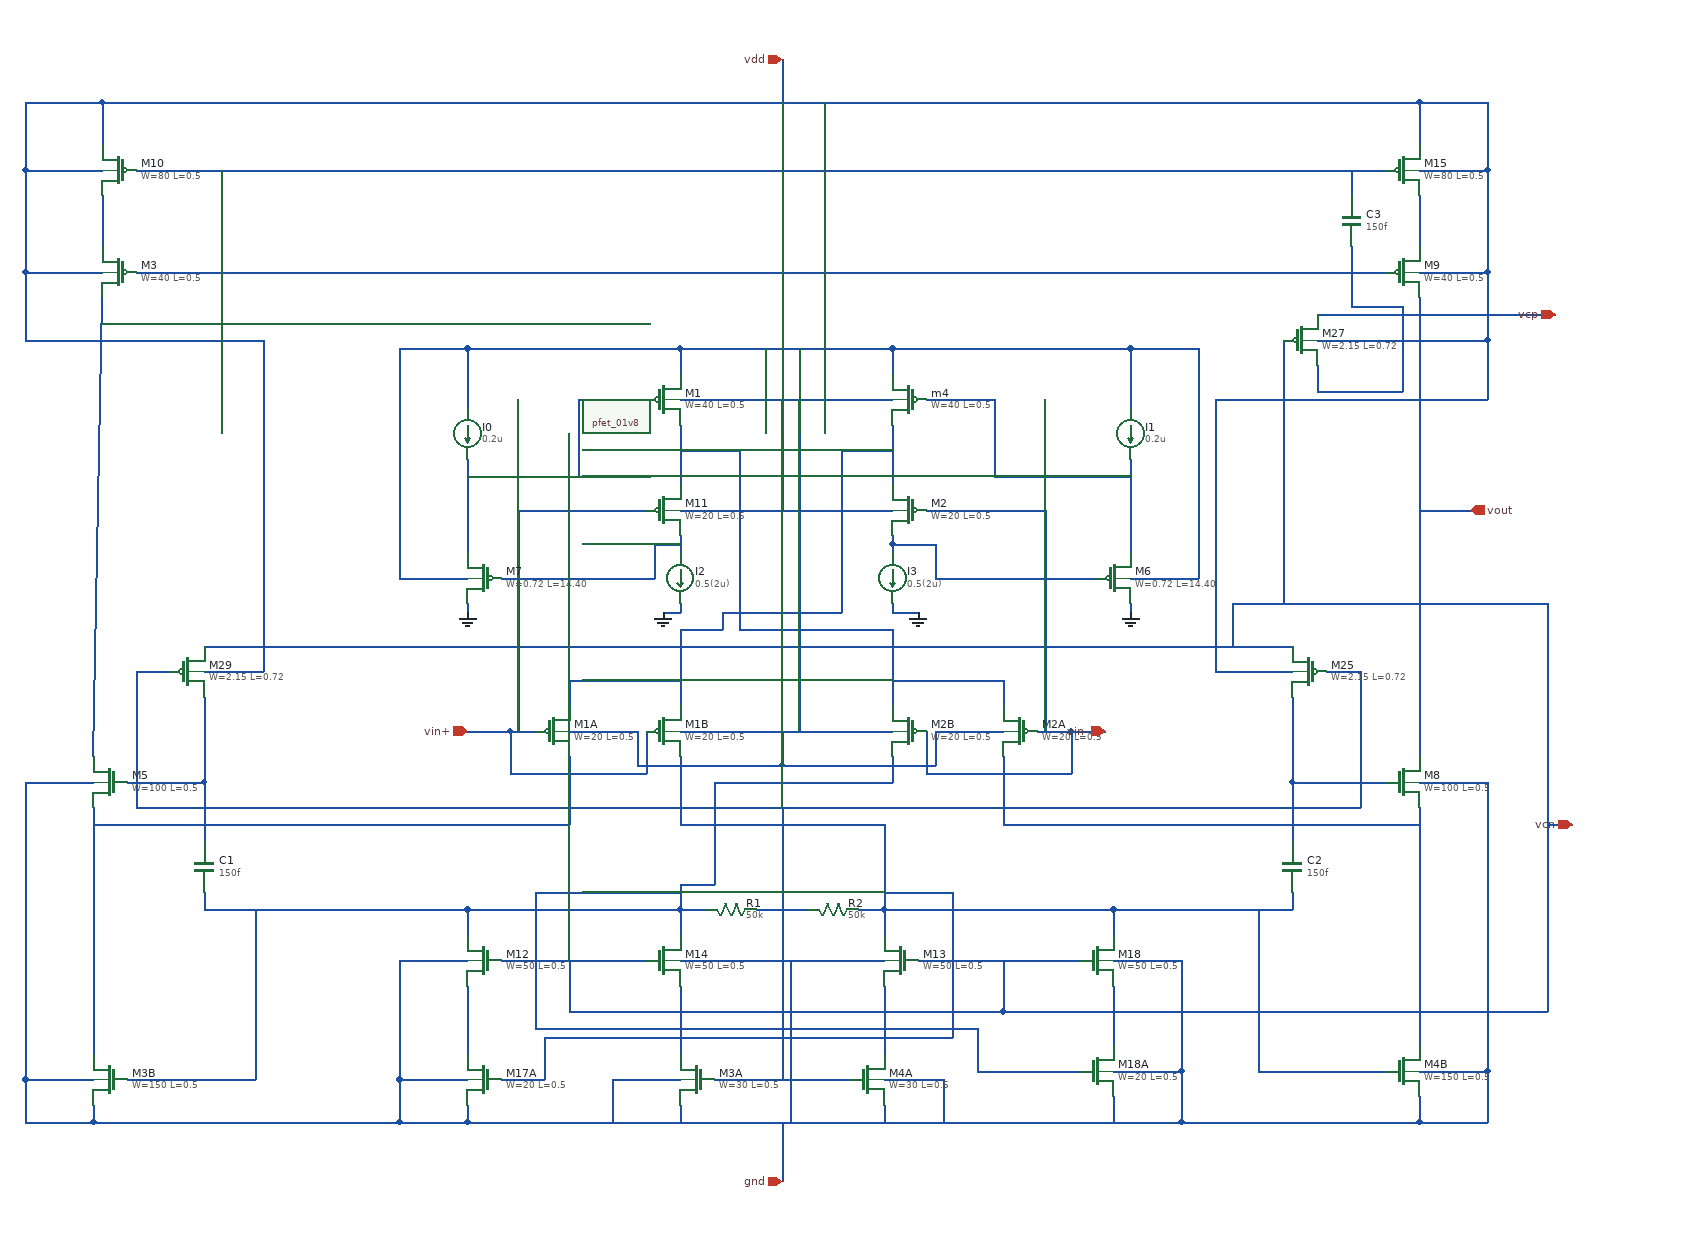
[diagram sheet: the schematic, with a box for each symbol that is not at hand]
v {xschem version=3.4.8RC file_version=1.3}
G {}
K {}
V {}
S {.include /home/aryan_r_gowda/VLSI/pdk/volare/sky130/versions/0fe599b2afb6708d281543108caf8310912f54af/sky130A/libs.tech/ngspice/sky130.lib.spice
.lib /home/aryan_r_gowda/VLSI/pdk/volare/sky130/versions/0fe599b2afb6708d281543108caf8310912f54af/sky130A/libs.tech/ngspice/sky130.lib.spice tt}
F {}
E {}
N -120 -270 -120 -240 {lab=vdd}
N -120 -270 130 -270 {lab=vdd}
N 130 -270 130 -240 {lab=vdd}
N 130 -180 130 -110 {lab=#net1}
N 260 120 260 150 {lab=#net2}
N 130 120 260 120 {lab=#net2}
N -250 120 -250 150 {lab=#net1}
N -250 120 -120 120 {lab=#net1}
N 130 100 130 150 {lab=#net2}
N -120 -150 -80 -150 {lab=#net2}
N -120 100 -120 150 {lab=#net1}
N 90 -150 130 -150 {lab=#net1}
N -370 -270 -370 -200 {lab=vdd}
N -370 -270 -120 -270 {lab=vdd}
N 410 -270 410 -200 {lab=vdd}
N 130 -270 330 -270 {lab=vdd}
N -370 -140 -370 -30 {lab=#net3}
N 410 -140 410 -30 {lab=#net4}
N 130 -50 130 -40 {lab=#net5}
N -160 180 -160 230 {lab=vin+}
N -320 230 -160 230 {lab=vin+}
N -320 180 -320 230 {lab=vin+}
N -320 180 -290 180 {lab=vin+}
N -370 180 -320 180 {lab=vin+}
N -120 60 -120 100 {lab=#net1}
N 130 60 130 100 {lab=#net2}
N 170 180 170 230 {lab=vin-}
N 170 230 340 230 {lab=vin-}
N 340 180 340 230 {lab=vin-}
N 300 180 340 180 {lab=vin-}
N 340 180 380 180 {lab=vin-}
N 330 -270 410 -270 {lab=vdd}
N 170 -80 310 -80 {lab=vin-}
N 310 -80 310 180 {lab=vin-}
N 170 -210 250 -210 {lab=#net4}
N 320 -120 410 -120 {lab=#net4}
N -240 -210 -160 -210 {lab=#net3}
N -370 -120 -310 -120 {lab=#net3}
N -370 30 -370 40 {lab=0}
N -120 30 -120 40 {lab=0}
N -140 40 -120 40 {lab=0}
N 410 30 410 40 {lab=0}
N -120 -210 130 -210 {lab=vdd}
N -120 180 130 180 {lab=vdd}
N -120 -180 -120 -110 {lab=#net2}
N -310 -80 -160 -80 {lab=vin+}
N -310 -80 -310 -60 {lab=vin+}
N -310 -60 -310 180 {lab=vin+}
N -120 -80 130 -80 {lab=vdd}
N -450 -0 -370 -0 {lab=vdd}
N -450 -270 -370 -270 {lab=vdd}
N 410 -0 490 -0 {lab=vdd}
N 490 -270 490 -0 {lab=vdd}
N 410 -270 490 -270 {lab=vdd}
N -250 180 -180 180 {lab=vdd}
N -180 180 -170 180 {lab=vdd}
N -170 180 -170 220 {lab=vdd}
N -170 220 -0 220 {lab=vdd}
N -0 180 -0 220 {lab=vdd}
N 180 180 260 180 {lab=vdd}
N 180 180 180 220 {lab=vdd}
N 0 220 180 220 {lab=vdd}
N -20 -270 -20 -210 {lab=vdd}
N -0 -270 0 -80 {lab=vdd}
N 20 -270 20 180 {lab=vdd}
N -120 480 -120 560 {lab=#net6}
N 120 480 120 550 {lab=#net7}
N 390 480 390 550 {lab=#net8}
N 160 450 350 450 {lab=vcn}
N -330 450 -160 450 {lab=vcn}
N -370 620 -370 640 {lab=gnd}
N -360 640 400 640 {lab=gnd}
N 390 610 390 640 {lab=gnd}
N -120 620 -120 640 {lab=gnd}
N -80 590 80 590 {lab=#net9}
N 120 550 120 560 {lab=#net7}
N 120 620 120 640 {lab=gnd}
N -250 450 -250 510 {lab=vcn}
N -120 390 -120 420 {lab=#net10}
N -120 390 -90 390 {lab=#net10}
N -30 390 30 390 {lab=#net9}
N 90 390 120 390 {lab=#net11}
N 120 390 120 420 {lab=#net11}
N -0 390 -0 590 {lab=#net9}
N -450 450 -370 450 {lab=gnd}
N -450 450 -450 590 {lab=gnd}
N -450 590 -370 590 {lab=gnd}
N -450 590 -450 640 {lab=gnd}
N -450 640 -370 640 {lab=gnd}
N -120 450 120 450 {lab=gnd}
N 10 450 120 450 {lab=gnd}
N 10 450 10 640 {lab=gnd}
N -200 590 -120 590 {lab=gnd}
N -200 590 -200 640 {lab=gnd}
N 120 590 190 590 {lab=gnd}
N 190 590 190 640 {lab=gnd}
N 390 450 470 450 {lab=gnd}
N 470 450 470 580 {lab=gnd}
N 390 580 470 580 {lab=gnd}
N 470 580 470 640 {lab=gnd}
N 390 640 470 640 {lab=gnd}
N -120 210 -120 240 {lab=#net11}
N 130 210 130 240 {lab=#net10}
N -120 360 -120 390 {lab=#net10}
N -370 390 -370 420 {lab=#net10}
N -370 390 -120 390 {lab=#net10}
N 390 390 390 420 {lab=#net11}
N 120 390 390 390 {lab=#net11}
N -810 620 -810 640 {lab=gnd}
N -810 640 -450 640 {lab=gnd}
N 750 360 750 550 {lab=#net12}
N 750 610 750 640 {lab=gnd}
N 470 640 750 640 {lab=gnd}
N -680 390 -370 390 {lab=#net10}
N 390 390 600 390 {lab=#net11}
N -770 590 -740 590 {lab=#net10}
N -250 210 -250 290 {lab=#net13}
N -810 290 -250 290 {lab=#net13}
N 750 270 750 360 {lab=#net12}
N 260 210 260 290 {lab=#net12}
N 260 290 750 290 {lab=#net12}
N 600 370 600 390 {lab=#net11}
N -680 370 -680 390 {lab=#net10}
N 680 580 710 580 {lab=#net11}
N 600 240 600 310 {lab=#net14}
N 600 240 710 240 {lab=#net14}
N -680 240 -680 310 {lab=#net15}
N -770 240 -680 240 {lab=#net15}
N -890 240 -810 240 {lab=gnd}
N -890 240 -890 590 {lab=gnd}
N -890 590 -810 590 {lab=gnd}
N 750 580 830 580 {lab=gnd}
N 830 240 830 580 {lab=gnd}
N 750 240 830 240 {lab=gnd}
N -890 590 -890 640 {lab=gnd}
N -890 640 -810 640 {lab=gnd}
N 750 640 830 640 {lab=gnd}
N 830 580 830 640 {lab=gnd}
N 750 -330 750 210 {lab=vout}
N 750 -450 750 -390 {lab=#net16}
N -760 -360 710 -360 {lab=#net17}
N -760 -480 710 -480 {lab=#net18}
N -810 210 -800 -330 {lab=#net19}
N -800 -450 -800 -390 {lab=#net20}
N -800 -560 -800 -510 {lab=vdd}
N -800 -560 750 -560 {lab=vdd}
N 750 -560 750 -510 {lab=vdd}
N -660 -480 -660 -300 {lab=#net18}
N -800 -300 -660 -300 {lab=#net18}
N 600 140 600 240 {lab=#net14}
N 630 -250 630 -220 {lab=#net17}
N 630 -220 730 -220 {lab=#net17}
N 730 -300 730 -220 {lab=#net17}
N 730 -320 730 -300 {lab=#net17}
N 670 -320 730 -320 {lab=#net17}
N 670 -360 670 -320 {lab=#net17}
N 670 -390 670 -360 {lab=#net17}
N 670 -480 670 -450 {lab=#net18}
N -120 -50 -120 -30 {lab=#net21}
N -330 -0 -150 0 {lab=#net21}
N -150 -40 -150 0 {lab=#net21}
N -150 -40 -120 -40 {lab=#net21}
N 180 -0 370 -0 {lab=#net5}
N 180 -40 180 -0 {lab=#net5}
N 130 -40 130 -30 {lab=#net5}
N 130 -40 180 -40 {lab=#net5}
N 130 30 130 40 {lab=0}
N 130 40 160 40 {lab=0}
N -680 160 -680 240 {lab=#net15}
N 750 -480 830 -480 {lab=vdd}
N 830 -480 830 -360 {lab=vdd}
N 750 -360 830 -360 {lab=vdd}
N 630 -280 830 -280 {lab=vdd}
N 830 -360 830 -280 {lab=vdd}
N -890 -360 -800 -360 {lab=vdd}
N -890 -480 -890 -360 {lab=vdd}
N -890 -480 -800 -480 {lab=vdd}
N -890 -560 -890 -480 {lab=vdd}
N -890 -560 -800 -560 {lab=vdd}
N 830 -560 830 -480 {lab=vdd}
N 750 -560 830 -560 {lab=vdd}
N 510 110 600 110 {lab=vdd}
N 510 -210 510 110 {lab=vdd}
N 510 -210 830 -210 {lab=vdd}
N 830 -280 830 -210 {lab=vdd}
N -890 -280 -610 -280 {lab=vdd}
N -890 -360 -890 -280 {lab=vdd}
N -0 -610 0 -560 {lab=vdd}
N 0 640 0 710 {lab=gnd}
N -250 510 260 510 {lab=vcn}
N 260 450 260 510 {lab=vcn}
N 260 510 900 510 {lab=vcn}
N -680 140 -680 160 {lab=#net15}
N -680 80 600 80 {lab=vcn}
N -680 110 -610 110 {lab=vdd}
N -610 -280 -610 110 {lab=vdd}
N 530 30 530 80 {lab=vcn}
N 530 30 900 30 {lab=vcn}
N 900 30 900 510 {lab=vcn}
N 900 290 930 290 {lab=vcn}
N 590 -280 590 30 {lab=vcn}
N 630 -310 910 -310 {lab=vcp}
N 750 -80 810 -80 {lab=vout}
N -330 590 -280 590 {lab=#net11}
N -280 540 -280 590 {lab=#net11}
N -280 540 200 540 {lab=#net11}
N 200 370 200 540 {lab=#net11}
N 230 580 350 580 {lab=#net10}
N 230 530 230 580 {lab=#net10}
N -290 530 230 530 {lab=#net10}
N -290 370 -290 530 {lab=#net10}
N -760 110 -720 110 {lab=#net9}
N 640 110 670 110 {lab=#net9}
N 50 -560 50 -270 {lab=vdd}
N -370 480 -370 560 {lab=#net22}
N -450 -10 -450 -0 {lab=vdd}
N -450 -270 -450 -10 {lab=vdd}
N -370 640 -360 640 {lab=gnd}
N -810 270 -810 560 {lab=#net13}
N -760 110 -760 140 {lab=#net9}
N -760 140 -760 210 {lab=#net9}
N -760 210 -760 270 {lab=#net9}
N -760 270 680 270 {lab=#net9}
N 680 110 680 270 {lab=#net9}
N 670 110 680 110 {lab=#net9}
N -0 270 0 390 {lab=#net9}
N -290 370 -120 370 {lab=#net10}
N 120 370 200 370 {lab=#net11}
N -740 590 -620 590 {lab=#net10}
N -620 390 -620 590 {lab=#net10}
N 560 580 680 580 {lab=#net11}
N 560 390 560 580 {lab=#net11}
N -120 240 -120 290 {lab=#net11}
N -120 290 120 290 {lab=#net11}
N 120 290 120 390 {lab=#net11}
N -80 240 130 240 {lab=#net10}
N -80 240 -80 360 {lab=#net10}
N -120 360 -80 360 {lab=#net10}
N -80 -150 -50 -150 {lab=#net2}
N -50 -150 -50 60 {lab=#net2}
N -50 60 130 60 {lab=#net2}
N -120 60 -70 60 {lab=#net1}
N -70 40 -70 60 {lab=#net1}
N -70 40 70 40 {lab=#net1}
N 70 -150 70 40 {lab=#net1}
N 70 -150 90 -150 {lab=#net1}
N -310 -120 -240 -120 {lab=#net3}
N -240 -210 -240 -120 {lab=#net3}
N 250 -120 320 -120 {lab=#net4}
N 250 -210 250 -120 {lab=#net4}
C {sky130_fd_pr/doc/pfet_01v8.svg} -120 -180 0 0 {}
C {sky130_fd_pr/pfet_01v8.sym} -140 -210 0 0 {name=M1
W=40
L=0.5
nf=1
mult=1
ad="'int((nf+1)/2) * W/nf * 0.29'" 
pd="'2*int((nf+1)/2) * (W/nf + 0.29)'"
as="'int((nf+2)/2) * W/nf * 0.29'" 
ps="'2*int((nf+2)/2) * (W/nf + 0.29)'"
nrd="'0.29 / W'" nrs="'0.29 / W'"
sa=0 sb=0 sd=0
model=pfet_01v8
spiceprefix=X
}
C {sky130_fd_pr/pfet_01v8.sym} -140 180 0 0 {name=M1B
W=20
L=0.5
nf=1
mult=1
ad="'int((nf+1)/2) * W/nf * 0.29'" 
pd="'2*int((nf+1)/2) * (W/nf + 0.29)'"
as="'int((nf+2)/2) * W/nf * 0.29'" 
ps="'2*int((nf+2)/2) * (W/nf + 0.29)'"
nrd="'0.29 / W'" nrs="'0.29 / W'"
sa=0 sb=0 sd=0
model=pfet_01v8
spiceprefix=X
}
C {sky130_fd_pr/pfet_01v8.sym} 150 -80 0 1 {name=M2

W=20
L=0.5
nf=1
mult=1
ad="'int((nf+1)/2) * W/nf * 0.29'" 
pd="'2*int((nf+1)/2) * (W/nf + 0.29)'"
as="'int((nf+2)/2) * W/nf * 0.29'" 
ps="'2*int((nf+2)/2) * (W/nf + 0.29)'"
nrd="'0.29 / W'" nrs="'0.29 / W'"
sa=0 sb=0 sd=0
model=pfet_01v8
spiceprefix=X
}
C {sky130_fd_pr/pfet_01v8.sym} 150 180 0 1 {name=M2B
W=20
L=0.5
nf=1
mult=1
ad="'int((nf+1)/2) * W/nf * 0.29'" 
pd="'2*int((nf+1)/2) * (W/nf + 0.29)'"
as="'int((nf+2)/2) * W/nf * 0.29'" 
ps="'2*int((nf+2)/2) * (W/nf + 0.29)'"
nrd="'0.29 / W'" nrs="'0.29 / W'"
sa=0 sb=0 sd=0
model=pfet_01v8
spiceprefix=X
}
C {sky130_fd_pr/pfet_01v8.sym} 390 0 0 0 {name=M6
W=0.72
L=14.40
nf=1
mult=1
ad="'int((nf+1)/2) * W/nf * 0.29'" 
pd="'2*int((nf+1)/2) * (W/nf + 0.29)'"
as="'int((nf+2)/2) * W/nf * 0.29'" 
ps="'2*int((nf+2)/2) * (W/nf + 0.29)'"
nrd="'0.29 / W'" nrs="'0.29 / W'"
sa=0 sb=0 sd=0
model=pfet_01v8
spiceprefix=X
}
C {sky130_fd_pr/pfet_01v8.sym} -350 0 0 1 {name=M7
W=0.72
L=14.40
nf=1
mult=1
ad="'int((nf+1)/2) * W/nf * 0.29'" 
pd="'2*int((nf+1)/2) * (W/nf + 0.29)'"
as="'int((nf+2)/2) * W/nf * 0.29'" 
ps="'2*int((nf+2)/2) * (W/nf + 0.29)'"
nrd="'0.29 / W'" nrs="'0.29 / W'"
sa=0 sb=0 sd=0
model=pfet_01v8
spiceprefix=X
}
C {sky130_fd_pr/pfet_01v8.sym} 150 -210 0 1 {name=m4
W=40
L=0.5
nf=1
mult=1
ad="'int((nf+1)/2) * W/nf * 0.29'" 
pd="'2*int((nf+1)/2) * (W/nf + 0.29)'"
as="'int((nf+2)/2) * W/nf * 0.29'" 
ps="'2*int((nf+2)/2) * (W/nf + 0.29)'"
nrd="'0.29 / W'" nrs="'0.29 / W'"
sa=0 sb=0 sd=0
model=pfet_01v8
spiceprefix=X
}
C {sky130_fd_pr/pfet_01v8.sym} -270 180 0 0 {name=M1A
W=20
L=0.5
nf=1
mult=1
ad="'int((nf+1)/2) * W/nf * 0.29'" 
pd="'2*int((nf+1)/2) * (W/nf + 0.29)'"
as="'int((nf+2)/2) * W/nf * 0.29'" 
ps="'2*int((nf+2)/2) * (W/nf + 0.29)'"
nrd="'0.29 / W'" nrs="'0.29 / W'"
sa=0 sb=0 sd=0
model=pfet_01v8
spiceprefix=X
}
C {sky130_fd_pr/pfet_01v8.sym} 280 180 0 1 {name=M2A
W=20
L=0.5
nf=1
mult=1
ad="'int((nf+1)/2) * W/nf * 0.29'" 
pd="'2*int((nf+1)/2) * (W/nf + 0.29)'"
as="'int((nf+2)/2) * W/nf * 0.29'" 
ps="'2*int((nf+2)/2) * (W/nf + 0.29)'"
nrd="'0.29 / W'" nrs="'0.29 / W'"
sa=0 sb=0 sd=0
model=pfet_01v8
spiceprefix=X
}
C {isource.sym} -370 -170 0 0 {name=I0 value=0.2u}
C {isource.sym} 410 -170 0 0 {name=I1 value=0.2u}
C {isource.sym} -120 0 0 0 {name=I2 value=0.5(2u)}
C {isource.sym} 130 0 0 0 {name=I3 value=0.5(2u)}
C {gnd.sym} -370 40 0 0 {name=l1 lab=0}
C {gnd.sym} -140 40 0 0 {name=l2 lab=0}
C {gnd.sym} 410 40 0 0 {name=l4 lab=0}
C {sky130_fd_pr/nfet_01v8.sym} -350 590 0 1 {name=M17A
W=20
L=0.5
nf=1 
mult=1
ad="'int((nf+1)/2) * W/nf * 0.29'" 
pd="'2*int((nf+1)/2) * (W/nf + 0.29)'"
as="'int((nf+2)/2) * W/nf * 0.29'" 
ps="'2*int((nf+2)/2) * (W/nf + 0.29)'"
nrd="'0.29 / W'" nrs="'0.29 / W'"
sa=0 sb=0 sd=0
model=nfet_01v8
spiceprefix=X
}
C {sky130_fd_pr/nfet_01v8.sym} -350 450 0 1 {name=M12
W=50
L=0.5
nf=1 
mult=1
ad="'int((nf+1)/2) * W/nf * 0.29'" 
pd="'2*int((nf+1)/2) * (W/nf + 0.29)'"
as="'int((nf+2)/2) * W/nf * 0.29'" 
ps="'2*int((nf+2)/2) * (W/nf + 0.29)'"
nrd="'0.29 / W'" nrs="'0.29 / W'"
sa=0 sb=0 sd=0
model=nfet_01v8
spiceprefix=X
}
C {sky130_fd_pr/nfet_01v8.sym} 140 450 0 1 {name=M13
W=50
L=0.5
nf=1 
mult=1
ad="'int((nf+1)/2) * W/nf * 0.29'" 
pd="'2*int((nf+1)/2) * (W/nf + 0.29)'"
as="'int((nf+2)/2) * W/nf * 0.29'" 
ps="'2*int((nf+2)/2) * (W/nf + 0.29)'"
nrd="'0.29 / W'" nrs="'0.29 / W'"
sa=0 sb=0 sd=0
model=nfet_01v8
spiceprefix=X
}
C {sky130_fd_pr/nfet_01v8.sym} -140 450 0 0 {name=M14
W=50
L=0.5
nf=1 
mult=1
ad="'int((nf+1)/2) * W/nf * 0.29'" 
pd="'2*int((nf+1)/2) * (W/nf + 0.29)'"
as="'int((nf+2)/2) * W/nf * 0.29'" 
ps="'2*int((nf+2)/2) * (W/nf + 0.29)'"
nrd="'0.29 / W'" nrs="'0.29 / W'"
sa=0 sb=0 sd=0
model=nfet_01v8
spiceprefix=X
}
C {sky130_fd_pr/nfet_01v8.sym} 100 590 0 0 {name=M4A
W=30
L=0.5
nf=1 
mult=1
ad="'int((nf+1)/2) * W/nf * 0.29'" 
pd="'2*int((nf+1)/2) * (W/nf + 0.29)'"
as="'int((nf+2)/2) * W/nf * 0.29'" 
ps="'2*int((nf+2)/2) * (W/nf + 0.29)'"
nrd="'0.29 / W'" nrs="'0.29 / W'"
sa=0 sb=0 sd=0
model=nfet_01v8
spiceprefix=X
}
C {sky130_fd_pr/nfet_01v8.sym} -100 590 0 1 {name=M3A
W=30
L=0.5
nf=1 
mult=1
ad="'int((nf+1)/2) * W/nf * 0.29'" 
pd="'2*int((nf+1)/2) * (W/nf + 0.29)'"
as="'int((nf+2)/2) * W/nf * 0.29'" 
ps="'2*int((nf+2)/2) * (W/nf + 0.29)'"
nrd="'0.29 / W'" nrs="'0.29 / W'"
sa=0 sb=0 sd=0
model=nfet_01v8
spiceprefix=X
}
C {sky130_fd_pr/nfet_01v8.sym} 370 580 0 0 {name=M18A
W=20
L=0.5
nf=1 
mult=1
ad="'int((nf+1)/2) * W/nf * 0.29'" 
pd="'2*int((nf+1)/2) * (W/nf + 0.29)'"
as="'int((nf+2)/2) * W/nf * 0.29'" 
ps="'2*int((nf+2)/2) * (W/nf + 0.29)'"
nrd="'0.29 / W'" nrs="'0.29 / W'"
sa=0 sb=0 sd=0
model=nfet_01v8
spiceprefix=X
}
C {sky130_fd_pr/nfet_01v8.sym} 370 450 0 0 {name=M18
W=50
L=0.5
nf=1 
mult=1
ad="'int((nf+1)/2) * W/nf * 0.29'" 
pd="'2*int((nf+1)/2) * (W/nf + 0.29)'"
as="'int((nf+2)/2) * W/nf * 0.29'" 
ps="'2*int((nf+2)/2) * (W/nf + 0.29)'"
nrd="'0.29 / W'" nrs="'0.29 / W'"
sa=0 sb=0 sd=0
model=nfet_01v8
spiceprefix=X
}
C {res.sym} -60 390 1 0 {name=R1
value=50k
footprint=1206
device=resistor
m=1}
C {res.sym} 60 390 1 0 {name=R2
value=50k
footprint=1206
device=resistor
m=1}
C {sky130_fd_pr/nfet_01v8.sym} 730 240 0 0 {name=M8
W=100
L=0.5
nf=1 
mult=1
ad="'int((nf+1)/2) * W/nf * 0.29'" 
pd="'2*int((nf+1)/2) * (W/nf + 0.29)'"
as="'int((nf+2)/2) * W/nf * 0.29'" 
ps="'2*int((nf+2)/2) * (W/nf + 0.29)'"
nrd="'0.29 / W'" nrs="'0.29 / W'"
sa=0 sb=0 sd=0
model=nfet_01v8
spiceprefix=X
}
C {sky130_fd_pr/nfet_01v8.sym} 730 580 0 0 {name=M4B
W=150
L=0.5
nf=1 
mult=1
ad="'int((nf+1)/2) * W/nf * 0.29'" 
pd="'2*int((nf+1)/2) * (W/nf + 0.29)'"
as="'int((nf+2)/2) * W/nf * 0.29'" 
ps="'2*int((nf+2)/2) * (W/nf + 0.29)'"
nrd="'0.29 / W'" nrs="'0.29 / W'"
sa=0 sb=0 sd=0
model=nfet_01v8
spiceprefix=X
}
C {sky130_fd_pr/nfet_01v8.sym} -790 240 0 1 {name=M5
W=100
L=0.5
nf=1 
mult=1
ad="'int((nf+1)/2) * W/nf * 0.29'" 
pd="'2*int((nf+1)/2) * (W/nf + 0.29)'"
as="'int((nf+2)/2) * W/nf * 0.29'" 
ps="'2*int((nf+2)/2) * (W/nf + 0.29)'"
nrd="'0.29 / W'" nrs="'0.29 / W'"
sa=0 sb=0 sd=0
model=nfet_01v8
spiceprefix=X
}
C {sky130_fd_pr/nfet_01v8.sym} -790 590 0 1 {name=M3B
W=150
L=0.5
nf=1 
mult=1
ad="'int((nf+1)/2) * W/nf * 0.29'" 
pd="'2*int((nf+1)/2) * (W/nf + 0.29)'"
as="'int((nf+2)/2) * W/nf * 0.29'" 
ps="'2*int((nf+2)/2) * (W/nf + 0.29)'"
nrd="'0.29 / W'" nrs="'0.29 / W'"
sa=0 sb=0 sd=0
model=nfet_01v8
spiceprefix=X
}
C {capa.sym} -680 340 0 0 {name=C1
m=1
value=150f
footprint=1206
device="ceramic capacitor"}
C {capa.sym} 600 340 0 0 {name=C2
m=1
value=150f
footprint=1206
device="ceramic capacitor"}
C {sky130_fd_pr/pfet_01v8.sym} -780 -480 0 1 {name=M10
W=80
L=0.5
nf=1
mult=1
ad="'int((nf+1)/2) * W/nf * 0.29'" 
pd="'2*int((nf+1)/2) * (W/nf + 0.29)'"
as="'int((nf+2)/2) * W/nf * 0.29'" 
ps="'2*int((nf+2)/2) * (W/nf + 0.29)'"
nrd="'0.29 / W'" nrs="'0.29 / W'"
sa=0 sb=0 sd=0
model=pfet_01v8
spiceprefix=X
}
C {sky130_fd_pr/pfet_01v8.sym} -780 -360 0 1 {name=M3
W=40
L=0.5
nf=1
mult=1
ad="'int((nf+1)/2) * W/nf * 0.29'" 
pd="'2*int((nf+1)/2) * (W/nf + 0.29)'"
as="'int((nf+2)/2) * W/nf * 0.29'" 
ps="'2*int((nf+2)/2) * (W/nf + 0.29)'"
nrd="'0.29 / W'" nrs="'0.29 / W'"
sa=0 sb=0 sd=0
model=pfet_01v8
spiceprefix=X
}
C {sky130_fd_pr/pfet_01v8.sym} 620 110 0 1 {name=M25
W=2.15
L=0.72
nf=1
mult=1
ad="'int((nf+1)/2) * W/nf * 0.29'" 
pd="'2*int((nf+1)/2) * (W/nf + 0.29)'"
as="'int((nf+2)/2) * W/nf * 0.29'" 
ps="'2*int((nf+2)/2) * (W/nf + 0.29)'"
nrd="'0.29 / W'" nrs="'0.29 / W'"
sa=0 sb=0 sd=0
model=pfet_01v8
spiceprefix=X
}
C {sky130_fd_pr/pfet_01v8.sym} 730 -360 0 0 {name=M9
W=40
L=0.5
nf=1
mult=1
ad="'int((nf+1)/2) * W/nf * 0.29'" 
pd="'2*int((nf+1)/2) * (W/nf + 0.29)'"
as="'int((nf+2)/2) * W/nf * 0.29'" 
ps="'2*int((nf+2)/2) * (W/nf + 0.29)'"
nrd="'0.29 / W'" nrs="'0.29 / W'"
sa=0 sb=0 sd=0
model=pfet_01v8
spiceprefix=X
}
C {sky130_fd_pr/pfet_01v8.sym} 610 -280 0 0 {name=M27
W=2.15
L=0.72
nf=1
mult=1
ad="'int((nf+1)/2) * W/nf * 0.29'" 
pd="'2*int((nf+1)/2) * (W/nf + 0.29)'"
as="'int((nf+2)/2) * W/nf * 0.29'" 
ps="'2*int((nf+2)/2) * (W/nf + 0.29)'"
nrd="'0.29 / W'" nrs="'0.29 / W'"
sa=0 sb=0 sd=0
model=pfet_01v8
spiceprefix=X
}
C {sky130_fd_pr/pfet_01v8.sym} 730 -480 0 0 {name=M15
W=80
L=0.5
nf=1
mult=1
ad="'int((nf+1)/2) * W/nf * 0.29'" 
pd="'2*int((nf+1)/2) * (W/nf + 0.29)'"
as="'int((nf+2)/2) * W/nf * 0.29'" 
ps="'2*int((nf+2)/2) * (W/nf + 0.29)'"
nrd="'0.29 / W'" nrs="'0.29 / W'"
sa=0 sb=0 sd=0
model=pfet_01v8
spiceprefix=X
}
C {sky130_fd_pr/pfet_01v8.sym} -700 110 0 0 {name=M29
W=2.15
L=0.72
nf=1
mult=1
ad="'int((nf+1)/2) * W/nf * 0.29'" 
pd="'2*int((nf+1)/2) * (W/nf + 0.29)'"
as="'int((nf+2)/2) * W/nf * 0.29'" 
ps="'2*int((nf+2)/2) * (W/nf + 0.29)'"
nrd="'0.29 / W'" nrs="'0.29 / W'"
sa=0 sb=0 sd=0
model=pfet_01v8
spiceprefix=X
}
C {capa.sym} 670 -420 0 0 {name=C3
m=1
value=150f
footprint=1206
device="ceramic capacitor"}
C {gnd.sym} 160 40 0 0 {name=l3 lab=0}
C {ipin.sym} 930 290 2 0 {name=p1 lab=vcn}
C {ipin.sym} 910 -310 2 0 {name=p2 lab=vcp
}
C {ipin.sym} -370 180 0 0 {name=p3 lab=vin+}
C {ipin.sym} 380 180 2 0 {name=p4 lab=vin-}
C {ipin.sym} 0 -610 0 0 {name=p5 lab=vdd}
C {ipin.sym} 0 710 0 0 {name=p6 lab=gnd
}
C {opin.sym} 810 -80 0 0 {name=p7 lab=vout}
C {sky130_fd_pr/pfet_01v8.sym} -140 -80 0 0 {name=M11

W=20
L=0.5
nf=1
mult=1
ad="'int((nf+1)/2) * W/nf * 0.29'" 
pd="'2*int((nf+1)/2) * (W/nf + 0.29)'"
as="'int((nf+2)/2) * W/nf * 0.29'" 
ps="'2*int((nf+2)/2) * (W/nf + 0.29)'"
nrd="'0.29 / W'" nrs="'0.29 / W'"
sa=0 sb=0 sd=0
model=pfet_01v8
spiceprefix=X
}
